VERSION 5.7 ;
  NOWIREEXTENSIONATPIN ON ;
  DIVIDERCHAR "/" ;
  BUSBITCHARS "[]" ;
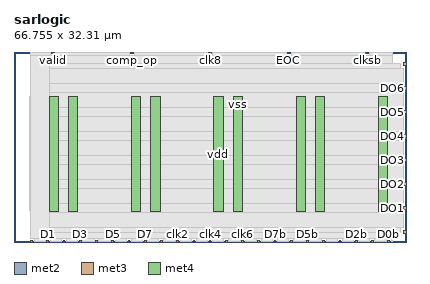
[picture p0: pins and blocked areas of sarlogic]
MACRO sarlogic
  CLASS BLOCK ;
  FOREIGN sarlogic ;
  ORIGIN 0.000 0.000 ;
  SIZE 66.755 BY 32.310 ;
  PIN D0
    DIRECTION OUTPUT ;
    USE SIGNAL ;
    ANTENNAGATEAREA 0.126000 ;
    ANTENNADIFFAREA 0.445500 ;
    PORT
      LAYER met2 ;
        RECT 2.850 0.000 3.130 0.280 ;
    END
  END D0
  PIN D0b
    DIRECTION OUTPUT ;
    USE SIGNAL ;
    ANTENNADIFFAREA 0.445500 ;
    PORT
      LAYER met2 ;
        RECT 63.570 0.000 63.850 0.280 ;
    END
  END D0b
  PIN D1
    DIRECTION OUTPUT ;
    USE SIGNAL ;
    ANTENNAGATEAREA 0.126000 ;
    ANTENNADIFFAREA 0.445500 ;
    PORT
      LAYER met2 ;
        RECT 5.610 0.000 5.890 0.280 ;
    END
  END D1
  PIN D1b
    DIRECTION OUTPUT ;
    USE SIGNAL ;
    ANTENNADIFFAREA 0.445500 ;
    PORT
      LAYER met2 ;
        RECT 60.810 0.000 61.090 0.280 ;
    END
  END D1b
  PIN D2
    DIRECTION OUTPUT ;
    USE SIGNAL ;
    ANTENNAGATEAREA 0.126000 ;
    ANTENNADIFFAREA 0.445500 ;
    PORT
      LAYER met2 ;
        RECT 8.370 0.000 8.650 0.280 ;
    END
  END D2
  PIN D2b
    DIRECTION OUTPUT ;
    USE SIGNAL ;
    ANTENNADIFFAREA 0.445500 ;
    PORT
      LAYER met2 ;
        RECT 58.050 0.000 58.330 0.280 ;
    END
  END D2b
  PIN D3
    DIRECTION OUTPUT ;
    USE SIGNAL ;
    ANTENNAGATEAREA 0.126000 ;
    ANTENNADIFFAREA 0.445500 ;
    PORT
      LAYER met2 ;
        RECT 11.130 0.000 11.410 0.280 ;
    END
  END D3
  PIN D3b
    DIRECTION OUTPUT ;
    USE SIGNAL ;
    ANTENNADIFFAREA 0.445500 ;
    PORT
      LAYER met2 ;
        RECT 55.290 0.000 55.570 0.280 ;
    END
  END D3b
  PIN D4
    DIRECTION OUTPUT ;
    USE SIGNAL ;
    ANTENNAGATEAREA 0.126000 ;
    ANTENNADIFFAREA 0.445500 ;
    PORT
      LAYER met2 ;
        RECT 13.890 0.000 14.170 0.280 ;
    END
  END D4
  PIN D4b
    DIRECTION OUTPUT ;
    USE SIGNAL ;
    ANTENNADIFFAREA 0.445500 ;
    PORT
      LAYER met2 ;
        RECT 52.530 0.000 52.810 0.280 ;
    END
  END D4b
  PIN D5
    DIRECTION OUTPUT ;
    USE SIGNAL ;
    ANTENNAGATEAREA 0.126000 ;
    ANTENNADIFFAREA 0.445500 ;
    PORT
      LAYER met2 ;
        RECT 16.650 0.000 16.930 0.280 ;
    END
  END D5
  PIN D5b
    DIRECTION OUTPUT ;
    USE SIGNAL ;
    ANTENNADIFFAREA 0.445500 ;
    PORT
      LAYER met2 ;
        RECT 49.770 0.000 50.050 0.280 ;
    END
  END D5b
  PIN D6
    DIRECTION OUTPUT ;
    USE SIGNAL ;
    ANTENNAGATEAREA 0.126000 ;
    ANTENNADIFFAREA 0.445500 ;
    PORT
      LAYER met2 ;
        RECT 19.410 0.000 19.690 0.280 ;
    END
  END D6
  PIN D6b
    DIRECTION OUTPUT ;
    USE SIGNAL ;
    ANTENNADIFFAREA 0.445500 ;
    PORT
      LAYER met2 ;
        RECT 47.010 0.000 47.290 0.280 ;
    END
  END D6b
  PIN D7
    DIRECTION OUTPUT ;
    USE SIGNAL ;
    ANTENNAGATEAREA 0.126000 ;
    ANTENNADIFFAREA 0.445500 ;
    PORT
      LAYER met2 ;
        RECT 22.170 0.000 22.450 0.280 ;
    END
  END D7
  PIN D7b
    DIRECTION OUTPUT ;
    USE SIGNAL ;
    ANTENNADIFFAREA 0.445500 ;
    PORT
      LAYER met2 ;
        RECT 44.250 0.000 44.530 0.280 ;
    END
  END D7b
  PIN DO0
    DIRECTION OUTPUT ;
    USE SIGNAL ;
    ANTENNADIFFAREA 0.445500 ;
    PORT
      LAYER met3 ;
        RECT 66.155 1.400 66.755 2.000 ;
    END
  END DO0
  PIN DO1
    DIRECTION OUTPUT ;
    USE SIGNAL ;
    ANTENNADIFFAREA 0.445500 ;
    PORT
      LAYER met3 ;
        RECT 66.155 5.480 66.755 6.080 ;
    END
  END DO1
  PIN DO2
    DIRECTION OUTPUT ;
    USE SIGNAL ;
    ANTENNADIFFAREA 0.445500 ;
    PORT
      LAYER met3 ;
        RECT 66.155 9.560 66.755 10.160 ;
    END
  END DO2
  PIN DO3
    DIRECTION OUTPUT ;
    USE SIGNAL ;
    ANTENNADIFFAREA 0.445500 ;
    PORT
      LAYER met3 ;
        RECT 66.155 13.640 66.755 14.240 ;
    END
  END DO3
  PIN DO4
    DIRECTION OUTPUT ;
    USE SIGNAL ;
    ANTENNADIFFAREA 0.445500 ;
    PORT
      LAYER met3 ;
        RECT 66.155 17.720 66.755 18.320 ;
    END
  END DO4
  PIN DO5
    DIRECTION OUTPUT ;
    USE SIGNAL ;
    ANTENNADIFFAREA 0.445500 ;
    PORT
      LAYER met3 ;
        RECT 66.155 21.800 66.755 22.400 ;
    END
  END DO5
  PIN DO6
    DIRECTION OUTPUT ;
    USE SIGNAL ;
    ANTENNADIFFAREA 0.445500 ;
    PORT
      LAYER met3 ;
        RECT 66.155 25.880 66.755 26.480 ;
    END
  END DO6
  PIN DO7
    DIRECTION OUTPUT ;
    USE SIGNAL ;
    ANTENNADIFFAREA 0.445500 ;
    PORT
      LAYER met3 ;
        RECT 66.155 29.960 66.755 30.560 ;
    END
  END DO7
  PIN EOC
    DIRECTION INPUT ;
    USE SIGNAL ;
    ANTENNAGATEAREA 1.272000 ;
    PORT
      LAYER met2 ;
        RECT 46.550 32.030 46.830 32.310 ;
    END
  END EOC
  PIN clk1
    DIRECTION OUTPUT ;
    USE SIGNAL ;
    ANTENNAGATEAREA 0.285000 ;
    ANTENNADIFFAREA 0.445500 ;
    PORT
      LAYER met2 ;
        RECT 24.930 0.000 25.210 0.280 ;
    END
  END clk1
  PIN clk2
    DIRECTION OUTPUT ;
    USE SIGNAL ;
    ANTENNAGATEAREA 0.285000 ;
    ANTENNADIFFAREA 0.445500 ;
    PORT
      LAYER met2 ;
        RECT 27.690 0.000 27.970 0.280 ;
    END
  END clk2
  PIN clk3
    DIRECTION OUTPUT ;
    USE SIGNAL ;
    ANTENNAGATEAREA 0.285000 ;
    ANTENNADIFFAREA 0.445500 ;
    PORT
      LAYER met2 ;
        RECT 30.450 0.000 30.730 0.280 ;
    END
  END clk3
  PIN clk4
    DIRECTION OUTPUT ;
    USE SIGNAL ;
    ANTENNAGATEAREA 0.285000 ;
    ANTENNADIFFAREA 0.445500 ;
    PORT
      LAYER met2 ;
        RECT 33.210 0.000 33.490 0.280 ;
    END
  END clk4
  PIN clk5
    DIRECTION OUTPUT ;
    USE SIGNAL ;
    ANTENNAGATEAREA 0.285000 ;
    ANTENNADIFFAREA 0.445500 ;
    PORT
      LAYER met2 ;
        RECT 35.970 0.000 36.250 0.280 ;
    END
  END clk5
  PIN clk6
    DIRECTION OUTPUT ;
    USE SIGNAL ;
    ANTENNAGATEAREA 0.285000 ;
    ANTENNADIFFAREA 0.445500 ;
    PORT
      LAYER met2 ;
        RECT 38.730 0.000 39.010 0.280 ;
    END
  END clk6
  PIN clk7
    DIRECTION OUTPUT ;
    USE SIGNAL ;
    ANTENNAGATEAREA 0.285000 ;
    ANTENNADIFFAREA 0.445500 ;
    PORT
      LAYER met2 ;
        RECT 41.490 0.000 41.770 0.280 ;
    END
  END clk7
  PIN clk8
    DIRECTION OUTPUT ;
    USE SIGNAL ;
    ANTENNAGATEAREA 0.159000 ;
    ANTENNADIFFAREA 0.445500 ;
    PORT
      LAYER met2 ;
        RECT 33.210 32.030 33.490 32.310 ;
    END
  END clk8
  PIN clksb
    DIRECTION INPUT ;
    USE SIGNAL ;
    ANTENNAGATEAREA 2.016000 ;
    PORT
      LAYER met2 ;
        RECT 59.890 32.030 60.170 32.310 ;
    END
  END clksb
  PIN comp_op
    DIRECTION INPUT ;
    USE SIGNAL ;
    ANTENNAGATEAREA 1.008000 ;
    PORT
      LAYER met2 ;
        RECT 19.870 32.030 20.150 32.310 ;
    END
  END comp_op
  PIN valid
    DIRECTION INPUT ;
    USE SIGNAL ;
    ANTENNAGATEAREA 1.272000 ;
    PORT
      LAYER met2 ;
        RECT 6.530 32.030 6.810 32.310 ;
    END
  END valid
  PIN vdd
    DIRECTION INOUT ;
    USE POWER ;
    PORT
      LAYER met4 ;
        RECT 5.960 5.200 7.560 24.720 ;
    END
    PORT
      LAYER met4 ;
        RECT 19.960 5.200 21.560 24.720 ;
    END
    PORT
      LAYER met4 ;
        RECT 33.960 5.200 35.560 24.720 ;
    END
    PORT
      LAYER met4 ;
        RECT 47.960 5.200 49.560 24.720 ;
    END
    PORT
      LAYER met4 ;
        RECT 61.960 5.200 63.560 24.720 ;
    END
  END vdd
  PIN vss
    DIRECTION INOUT ;
    USE GROUND ;
    PORT
      LAYER met4 ;
        RECT 9.260 5.200 10.860 24.720 ;
    END
    PORT
      LAYER met4 ;
        RECT 23.260 5.200 24.860 24.720 ;
    END
    PORT
      LAYER met4 ;
        RECT 37.260 5.200 38.860 24.720 ;
    END
    PORT
      LAYER met4 ;
        RECT 51.260 5.200 52.860 24.720 ;
    END
  END vss
  OBS
      LAYER nwell ;
        RECT 2.570 5.355 64.130 24.670 ;
      LAYER li1 ;
        RECT 2.760 5.355 63.940 24.565 ;
      LAYER met1 ;
        RECT 2.760 2.420 64.330 24.720 ;
      LAYER met2 ;
        RECT 2.860 31.750 6.250 32.240 ;
        RECT 7.090 31.750 19.590 32.240 ;
        RECT 20.430 31.750 32.930 32.240 ;
        RECT 33.770 31.750 46.270 32.240 ;
        RECT 47.110 31.750 59.610 32.240 ;
        RECT 60.450 31.750 64.310 32.240 ;
        RECT 2.860 0.560 64.310 31.750 ;
        RECT 3.410 0.070 5.330 0.560 ;
        RECT 6.170 0.070 8.090 0.560 ;
        RECT 8.930 0.070 10.850 0.560 ;
        RECT 11.690 0.070 13.610 0.560 ;
        RECT 14.450 0.070 16.370 0.560 ;
        RECT 17.210 0.070 19.130 0.560 ;
        RECT 19.970 0.070 21.890 0.560 ;
        RECT 22.730 0.070 24.650 0.560 ;
        RECT 25.490 0.070 27.410 0.560 ;
        RECT 28.250 0.070 30.170 0.560 ;
        RECT 31.010 0.070 32.930 0.560 ;
        RECT 33.770 0.070 35.690 0.560 ;
        RECT 36.530 0.070 38.450 0.560 ;
        RECT 39.290 0.070 41.210 0.560 ;
        RECT 42.050 0.070 43.970 0.560 ;
        RECT 44.810 0.070 46.730 0.560 ;
        RECT 47.570 0.070 49.490 0.560 ;
        RECT 50.330 0.070 52.250 0.560 ;
        RECT 53.090 0.070 55.010 0.560 ;
        RECT 55.850 0.070 57.770 0.560 ;
        RECT 58.610 0.070 60.530 0.560 ;
        RECT 61.370 0.070 63.290 0.560 ;
        RECT 64.130 0.070 64.310 0.560 ;
      LAYER met3 ;
        RECT 5.970 29.560 65.755 30.425 ;
        RECT 5.970 26.880 66.155 29.560 ;
        RECT 5.970 25.480 65.755 26.880 ;
        RECT 5.970 22.800 66.155 25.480 ;
        RECT 5.970 21.400 65.755 22.800 ;
        RECT 5.970 18.720 66.155 21.400 ;
        RECT 5.970 17.320 65.755 18.720 ;
        RECT 5.970 14.640 66.155 17.320 ;
        RECT 5.970 13.240 65.755 14.640 ;
        RECT 5.970 10.560 66.155 13.240 ;
        RECT 5.970 9.160 65.755 10.560 ;
        RECT 5.970 6.480 66.155 9.160 ;
        RECT 5.970 5.080 65.755 6.480 ;
        RECT 5.970 2.400 66.155 5.080 ;
        RECT 5.970 1.535 65.755 2.400 ;
  END
END sarlogic
END LIBRARY

